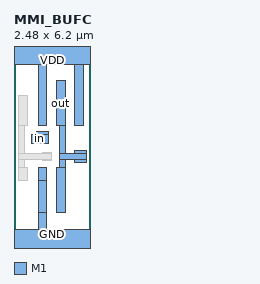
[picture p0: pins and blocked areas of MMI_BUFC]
MACRO MMI_BUFC
	CLASS CORE ;
	FOREIGN MMI_BUFC 0 0 ;
	SIZE 2.48 BY 6.2 ;
	SYMMETRY X Y ;
	SITE CORE1 ;
	PIN out
		DIRECTION output ;
		USE SIGNAL ;
		PORT
			LAYER M1 ;
			RECT 1.385 3.8 1.665 5.27 ;
			LAYER M1 ;
			RECT 1.475 2.885 1.665 3.8 ;
			LAYER M1 ;
			RECT 1.98 2.885 2.36 2.98 ;
			LAYER M1 ;
			RECT 1.475 2.695 2.36 2.885 ;
			LAYER M1 ;
			RECT 1.475 2.445 1.665 2.695 ;
			LAYER M1 ;
			RECT 1.98 2.6 2.36 2.695 ;
			LAYER M1 ;
			RECT 1.385 0.975 1.665 2.445 ;
		END
		AntennaDiffArea 1.2859 ;
	END out
	PIN GND
		DIRECTION inout ;
		USE GROUND ;
		PORT
			LAYER M1 ;
			RECT 0.795 1.995 1.075 2.445 ;
			LAYER M1 ;
			RECT 0.79 0.975 1.075 1.995 ;
			LAYER M1 ;
			RECT 0.79 0.42 1.07 0.975 ;
			LAYER M1 ;
			RECT 0 -0.42 2.48 0.42 ;
		END
	END GND
	PIN VDD
		DIRECTION inout ;
		USE POWER ;
		PORT
			LAYER M1 ;
			RECT 0 5.78 2.48 6.62 ;
			LAYER M1 ;
			RECT 0.795 3.8 1.075 5.78 ;
			LAYER M1 ;
			RECT 1.975 3.8 2.255 5.78 ;
		END
	END VDD
	PIN in
		DIRECTION input ;
		USE SIGNAL ;
		PORT
			LAYER M1 ;
			RECT 0.74 3.51 1.12 3.6 ;
			LAYER M1 ;
			RECT 0.56 3.23 1.12 3.51 ;
			LAYER M1 ;
			RECT 0.74 3.22 1.12 3.23 ;
		END
		AntennaGateArea 0.234 ;
	END in
	OBS
		LAYER M1 ;
		RECT 0.16 3.8 0.44 4.77 ;
		LAYER M1 ;
		RECT 0.16 2.885 0.355 3.8 ;
		LAYER M1 ;
		RECT 0.93 2.885 1.21 2.93 ;
		LAYER M1 ;
		RECT 0.16 2.695 1.21 2.885 ;
		LAYER M1 ;
		RECT 0.16 2.445 0.355 2.695 ;
		LAYER M1 ;
		RECT 0.93 2.65 1.21 2.695 ;
		LAYER M1 ;
		RECT 0.16 1.995 0.44 2.445 ;
	END
END MMI_BUFC
